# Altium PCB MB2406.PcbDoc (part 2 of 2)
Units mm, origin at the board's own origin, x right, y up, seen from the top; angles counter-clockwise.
Board outline 43 x 47 mm, 2 copper layers (Top Layer, Bottom Layer), stack 0.996 mm thick; 74 components, 55 nets, 319 pads, 911 vias.

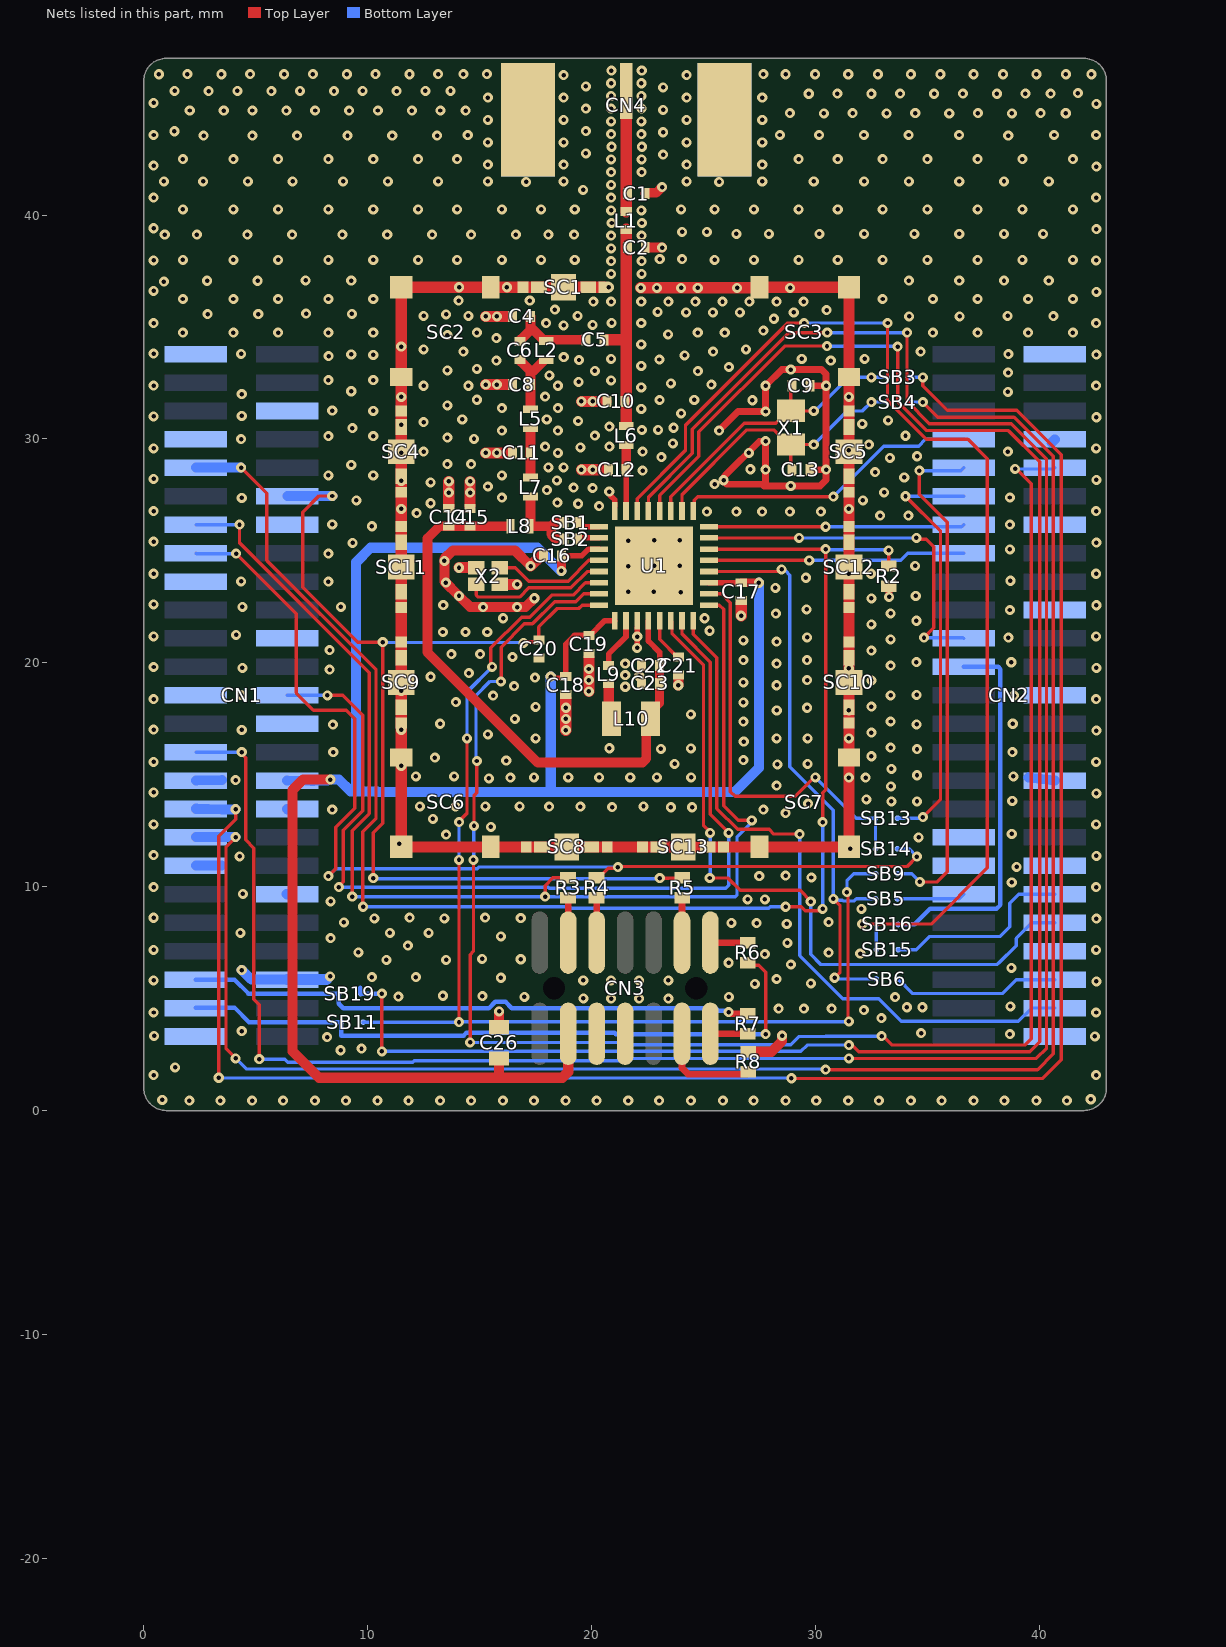
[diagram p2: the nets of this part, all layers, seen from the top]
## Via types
v1: diameter 0.45, hole 0.2, Top Layer to Bottom Layer, tented both sides, 911 vias

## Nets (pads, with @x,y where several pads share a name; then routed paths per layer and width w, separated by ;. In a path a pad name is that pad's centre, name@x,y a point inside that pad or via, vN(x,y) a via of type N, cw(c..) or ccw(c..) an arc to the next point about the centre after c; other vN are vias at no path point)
GND: C1.1 C2.1 C4.1 C8.1 C9.1 C10.1 C11.1 C12.1 C13.1 C14.2 C15.1 C16.1 C17.1 C18.1 C19.2 C20.1 C21.1 C22.1 C23.1 C26.1 CN1.1 CN1.6 CN1.7 CN1.14 CN1.17 CN1.22 CN1.25 CN1.28 CN1.31 CN1.34 CN1.37 CN1.40 CN1.46 CN1.49 CN2.2 CN2.8 CN2.14 CN2.20 CN2.26 CN2.32 CN2.38 CN2.44 CN2.50 CN3.5 CN3.7 CN4.2 CN4.3 CN4.4 CN4.5 R2.1 R8.1 SC1.1 SC2.1 SC3.1 SC4.1 SC5.1 SC6.1 SC7.1 SC8.1 SC9.1 SC10.1 SC11.1 SC12.1 SC13.1 U1.16 U1.27 U1.33 X2.2 X2.4 | length 148.5
  Top Layer w0.25: v1(20.793,27.649) 20.831,27.611 20.831,27.485 21.042,27.275 U1.16@21.042,27 ; v1(22.04,20.67) 22.041,20.671 v1(22.042,21.17) v1(22.042,21.17) U1.27@22.042,21.564
  Top Layer w0.3: v1@16.675,23.5 v1(16.68,23.505) ; v1(25.696,30.374) 26.547,31.225 v1(27.775,31.225) v1(27.775,32.375) 28.5,33.1 v1(28.9,33.1) 30.275,33.1 30.475,32.9 v1(30.475,32.375) ; C13.1@29.8,28.625 v1(30.475,28.625) ; C9.1@29.8,32.375 v1(30.475,32.375) ; R2.1@33.275,23.425 33.286,23.414 33.286,22.956 v1(33.297,22.945) ; 27.775,27.975 26.118,27.975 cw(c26.118,28.2) 25.959,28.359 27.491,29.891 27.766,29.891 v1(27.775,29.9) v1(27.775,28.625) 27.775,27.975 ; 27.775,27.975 27.7,27.9 v1(28.9,27.9) 30.214,27.9 30.475,28.161 v1(30.475,28.625) ; v1(30.475,28.625) v1(30.475,32.375)
  Top Layer w0.43: C1.1@22.4,40.961 22.4,40.981 22.415,40.996 22.895,40.996 23.15,41.25 v1(23.155,41.25) ; C2.1@22.45,38.55 v1(23.155,38.55)
  Top Layer w0.45: v1(14.08,24.245) v1@14.085,24.25 ; C26.1@15.875,3.725 v1(15.875,4.43) ; v1(17.275,24.32) 16.57,25.025 13.809,25.025 13.425,24.642 13.425,23.642 v1(14.08,22.988) 14.58,22.488 v1(15.155,22.488) v1(16.68,22.488) 17.053,22.488 v1(17.449,22.883) ; v1(23.874,18.996) 23.88,19.003 C21.1@23.88,19.339 ; R8.1@27.003,2.625 28.04,2.625 28.511,3.097 v1(28.511,3.34)
  Top Layer w0.5: C14.2@13.625,27 v1(13.625,27.6) v1(13.625,28.1) ; v1@14.085,24.25 X2.4@14.855,24.25 ; C15.1@14.575,27 v1(14.575,27.6) v1(14.575,28.1) ; v1(15.275,29.375) v1(15.775,29.375) C11.1@16.375,29.375 ; v1(15.275,32.425) v1(15.775,32.425) C8.1@16.375,32.425 ; v1(15.275,35.475) v1(15.775,35.475) C4.1@16.375,35.475 ; X2.2@15.905,23.5 v1@16.675,23.5 ; SC1.1@16.94,36.775 v1(16.22,36.775) SC2.1@15.5,36.775 SC2.1@11.5,36.775 v1(11.5,34.125) SC2.1@11.5,32.775 SC4.1@11.5,31.243 SC4.1@11.5,30.533 SC4.1@11.5,29.433 v1(11.5,29.375) SC4.1@11.5,28.333 SC4.1@11.5,27.623 SC11.1@11.5,26.088 SC11.1@11.5,25.378 SC11.1@11.5,24.278 SC11.1@11.5,23.178 SC11.1@11.5,22.468 SC9.1@11.5,20.93 SC9.1@11.5,20.22 SC9.1@11.5,19.12 SC9.1@11.5,18.02 SC9.1@11.5,17.31 SC6.1@11.5,15.775 v1(11.5,15.395) SC6.1@11.5,11.775 SC6.1@15.5,11.775 19.69,11.775 23.31,11.775 SC7.1@27.5,11.775 SC7.1@31.5,11.775 v1(31.5,14.875) SC7.1@31.5,15.775 v1(31.5,16.625) v1(31.5,17.875) v1(31.5,19.75) 31.5,22.464 SC12.1@31.5,22.468 SC12.1@31.5,23.178 v1(31.5,23.977) SC12.1@31.5,24.278 31.5,24.578 31.5,25.078 SC12.1@31.5,25.378 SC12.1@31.5,26.088 v1(31.5,26.875) SC5.1@31.5,27.623 SC5.1@31.5,28.333 SC5.1@31.5,29.433 SC5.1@31.5,30.533 SC5.1@31.5,31.243 SC3.1@31.5,32.775 SC3.1@31.5,36.775 SC3.1@27.5,36.775 ; SC1.1@16.94,36.775 SC1.1@17.65,36.775 SC1.1@18.75,36.775 SC1.1@19.85,36.775 SC1.1@20.56,36.775 ; v1(17.275,24.32) 17.731,24.776 C16.1@17.759,24.776 ; v1(18.852,16.99) v1(18.852,17.49) v1(18.852,17.99) C18.1@18.852,18.39 ; v1(19.55,28.625) v1(20.05,28.625) C12.1@20.65,28.625 ; v1(19.55,31.675) v1(20.05,31.675) C10.1@20.65,31.675 ; v1(19.882,18.723) v1(19.882,19.223) v1(19.882,19.723) C19.2@19.882,20.223 ; v1(22.2,36.75) v1(24.743,36.75) v1(26.5,36.75) SC3.1@27.475,36.75 ; v1(26.685,22.1) C17.1@26.685,22.675
  Bottom Layer w0.45: CN1.37@2.343,10.94 CN1.37@3.462,10.943 ; CN1.31@2.343,14.75 CN1.31@3.501,14.762 ; CN1.37@3.463,10.943 cw(c3.463,10.643) CN1.37@3.465,10.943 ; v1(4.375,6.275) 4.802,5.848 CN1.46@6.401,5.848 ; CN1.40@6.381,9.678 CN1.40@6.401,9.658 ; CN1.34@6.401,13.468 CN1.34@6.432,13.437 ; CN2.32@39.521,14.883 CN2.32@40.691,14.738 ; CN2.8@40.546,29.833 CN2.8@40.691,29.978
  Bottom Layer w0.5: CN1.46@6.401,5.848 8.16,5.848 v1@8.187,5.875
  other v1: 2.04,0.447 3.425,0.447 4.84,0.447 6.224,0.447 7.64,0.447 9.024,0.447 10.44,0.447 11.824,0.447 13.24,0.447 14.624,0.447 16.04,0.447 17.424,0.447 18.839,0.447 20.224,0.447 21.639,0.447 23.023,0.447 24.439,0.447 25.869,0.447 27.239,0.447 28.669,0.447 30.039,0.447 31.468,0.447 32.839,0.447 34.268,0.447 35.638,0.447 37.068,0.447 38.438,0.447 39.868,0.447 41.238,0.447 0.825,0.475 42.3,0.504 0.438,1.579 42.538,1.579 1.4,1.924 8.795,2.694 9.725,2.764 8.187,3.281 42.482,3.311 0.463,3.336 38.684,3.417 34.722,3.454 4.375,3.55 32.947,4.125 0.438,4.378 42.538,4.378 32.168,4.484 28.355,4.554 29.488,4.553 30.725,4.554 34.085,4.612 34.779,4.612 38.709,4.65 20.875,5 22.125,5 23.437,5 19.64,5.013 16.999,5.079 26.14,5.079 33.563,5.066 11.375,5.092 13.365,5.128 15.125,5.113 27.298,5.659 29.801,5.676 42.553,5.77 0.438,5.812 19.632,5.812 20.875,5.813 22.125,5.813 23.437,5.813 28.27,5.875 15.95,5.931 10.189,5.96 12.15,5.96 8.324,5.987 38.759,6.368 28.905,6.523 26.125,6.6 10.837,6.729 13.5,6.729 15.114,6.777 16.84,6.758 27.746,6.99 32.005,7.005 9.588,7.06 30.593,7.057 0.438,7.178 42.538,7.178 11.8,7.362 28.75,7.488 8.345,7.704 15.95,7.775 4.313,7.934 10.993,7.934 12.725,7.934 28.72,8.341 26.25,8.379 27.37,8.37 8.938,8.402 30.593,8.417 42.553,8.57 10.3,8.587 13.425,8.587 16.84,8.592 0.438,8.612 11.875,8.616 15.25,8.616 32.057,9.008 8.348,9.343 26.975,9.435 27.746,9.435 4.426,9.678 0.438,9.978 42.538,9.978 38.772,10.194 29.818,10.409 27.491,10.472 28.668,10.493 38.99,10.886 4.279,11.354 42.553,11.37 0.438,11.412 31.556,11.688 11.416,11.908 34.614,12.198 13.5,12.325 38.772,12.353 15.504,12.667 0.438,12.778 42.538,12.778 12.909,13.029 28.673,13.285 8.42,13.437 27.675,13.437 20.917,13.556 23.542,13.546 24.497,13.546 12.33,13.588 13.926,13.588 15.261,13.588 16.784,13.588 18.105,13.572 19.506,13.572 22.322,13.583 29.675,13.707 33.396,13.806 34.538,13.806 38.793,13.835 32.275,13.897 42.553,14.17 0.438,14.212 33.376,14.477 28.27,14.51 4.101,14.762 15.419,14.832 16.375,14.875 17.431,14.883 18.96,14.882 20.34,14.882 21.731,14.882 22.917,14.882 24.451,14.883 32.243,14.871 12.15,14.925 13.863,14.925 38.846,14.925 34.538,14.977 33.396,15.264 28.298,15.462 23.708,15.488 29.65,15.488 0.438,15.578 42.538,15.578 16.19,15.633 26.783,15.651 13,15.76 32.5,15.825 8.463,16.008 38.799,16.008 23.1,16.15 34.538,16.142 24.439,16.175 20.801,16.182 33.361,16.212 26.799,16.481 17.5,16.625 28.27,16.625 29.65,16.625 15.375,16.8 32.5,16.881 42.553,16.97 0.438,17.012 4.375,17 11.5,17 8.449,17.242 34.519,17.25 13.24,17.278 38.817,17.278 26.783,17.375 33.361,17.377 16.574,17.49 24.439,17.695 28.275,17.875 29.634,17.99 17.5,18.028 32.5,18.046 26.783,18.23 13.943,18.245 0.438,18.378 42.538,18.378 15.601,18.538 38.877,18.538 4.35,18.56 33.361,18.548 34.519,18.57 11.5,18.75 21.508,18.93 16.545,18.962 28.27,18.996 26.783,19.127 29.634,19.223 32.5,19.217 17.475,19.336 12.812,19.376 22.133,19.4 21.508,19.452 14.522,19.539 8.301,19.697 4.401,19.772 42.553,19.77 0.438,19.812 33.361,19.872 21.508,19.962 28.27,19.962 34.512,20.033 38.748,20.025 26.783,20.123 29.625,20.123 16.47,20.258 13.741,20.386 15.02,20.386 32.5,20.541 8.301,20.569 28.27,20.944 26.783,20.997 33.361,21.043 38.625,21.125 29.634,21.134 0.438,21.177 42.538,21.177 4.125,21.25 13.365,21.375 14.371,21.375 15.342,21.375 25.273,21.433 32.5,21.712 34.512,21.877 16.05,21.988 25.05,21.988 28.237,22.196 33.361,22.208 38.684,22.358 29.604,22.389 4.401,22.497 8.802,22.497 13.375,22.575 42.553,22.569 0.438,22.611 32.5,22.877 34.482,22.988 23.981,23.152 21.64,23.175 22.783,23.175 28.212,23.35 13.49,23.577 4.35,23.64 8.25,23.625 38.709,23.664 29.574,23.8 0.438,23.977 32.475,23.977 42.538,23.977 21.64,24.318 22.792,24.327 23.935,24.327 34.454,24.327 13.425,24.55 8.25,24.875 38.687,25.063 9.33,25.355 42.553,25.369 0.438,25.411 21.637,25.459 22.792,25.47 23.935,25.47 10.189,26.098 8.42,26.18 38.684,26.168 32.892,26.575 34.157,26.575 12.187,26.688 25.157,26.75 26.475,26.75 27.622,26.75 28.86,26.75 30.243,26.75 0.438,26.777 42.538,26.777 11.5,26.875 20.34,27 12.812,27.125 19.4,27.103 18.476,27.159 9.5,27.25 32.125,27.25 4.375,27.369 16,27.375 38.687,27.383 33.073,27.611 18.006,27.717 20.05,27.808 19.2,27.825 15.375,27.875 25.5,27.983 12.812,28.062 11.5,28.125 18.45,28.144 25.898,28.152 42.553,28.169 0.438,28.211 33.971,28.284 8.25,28.375 10.25,28.375 16,28.375 32.671,28.519 22.283,28.587 27.093,28.645 18.071,28.729 18.75,28.729 9.268,28.841 13.563,28.875 14.625,28.875 33.327,29.15 23.123,29.183 34.541,29.224 18.5,29.375 27.025,29.375 12.5,29.438 22.279,29.435 38.597,29.432 31.5,29.5 0.438,29.577 42.538,29.577 19.5,29.625 17.926,29.654 20.797,29.654 32.394,29.746 23.633,29.801 4.35,29.99 14.75,30 13.563,30.063 8.25,30.125 10.25,30.125 20.148,30.15 34.025,30.14 16,30.375 18.5,30.375 22.248,30.399 22.974,30.4 9.316,30.486 23.67,30.5 20.801,30.55 11.5,30.625 32.093,30.675 12.5,30.75 19.4,30.8 33.25,30.825 14.225,30.875 18,30.875 42.553,30.969 0.438,31.011 4.375,31.032 24,31.141 8.42,31.26 10.25,31.25 22.221,31.34 16,31.375 18.5,31.375 13.563,31.5 14.875,31.75 23.039,31.739 24.59,31.745 27.189,31.727 11.5,31.875 31.5,31.875 17.925,31.891 4.375,32 38.597,32.105 9.268,32.13 22.221,32.299 0.438,32.377 12.5,32.375 14.5,32.375 18.5,32.375 42.538,32.377 25.35,32.425 23.542,32.477 19.425,32.55 8.25,32.625 10.25,32.625 20.879,32.615 18.121,32.837 38.613,32.959 20.15,33.038 24.748,33.028 13.563,33.062 14.875,33.125 26.14,33.212 22.221,33.259 15.75,33.5 30.686,33.5 19.44,33.525 23.03,33.548 20.879,33.575 29.39,33.575 32.199,33.575 18.76,33.65 8.256,33.7 24.155,33.73 10.25,33.75 9.268,33.775 42.553,33.769 4.35,33.8 38.625,33.788 0.438,33.811 14.273,33.897 25.432,33.897 34.702,33.897 12.5,34 26.9,34 22.221,34.219 15.75,34.5 13.563,34.635 23.425,34.673 1.75,34.75 4,34.75 6,34.75 8.25,34.75 10.25,34.75 14.875,34.75 24.746,34.75 25.95,34.75 35.25,34.75 37.25,34.75 39.5,34.75 41.5,34.75 27.675,34.839 18.75,35.068 20.05,35.097 0.438,35.177 17.975,35.173 22.221,35.178 42.538,35.177 20.895,35.187 28.143,35.369 34.186,35.475 36.446,35.475 40.629,35.484 12.5,35.5 14.5,35.5 19.375,35.5 38.585,35.494 2.854,35.579 5.114,35.579 13.5,35.562 7.253,35.598 9.297,35.589 24.221,35.653 25.425,35.653 26.625,35.65 29.033,35.65 22.954,35.676 30.5,35.75 18.359,35.772 20.087,36.138 20.879,36.138 22.221,36.138 23.43,36.138 24.64,36.138 25.85,36.138 27.055,36.138 28.265,36.138 29.474,36.138 14.062,36.175 17.239,36.175 1.75,36.25 4,36.25 6,36.25 8.25,36.25 10.25,36.25 33,36.25 35.25,36.25 37.25,36.25 39.5,36.25 41.5,36.25 42.553,36.569 0.438,36.611 22.917,36.75 24,36.75 28.875,36.75 14.085,36.775 20.775,36.775 0.9,37.025 2.825,37.066 5.085,37.066 9.268,37.075 34.175,37.075 36.425,37.075 38.425,37.075 40.425,37.075 7.224,37.085 20.879,37.375 22.233,37.375 20.879,37.943 22.233,37.943 0.438,37.976 42.538,37.976 1.75,38 4,38 6,38 8.25,38 10.25,38 12.25,38 14,38 16,38 17.75,38 19.25,38 25.5,38 27.25,38 29.25,38 31,38 33,38 35,38 37.25,38 39.25,38 41.5,38 23.048,38.029 24.05,38.029 20.879,38.51 20.879,39.078 22.233,39.078 0.936,39.125 2.375,39.125 4.625,39.125 6.625,39.125 8.875,39.125 10.875,39.125 12.875,39.125 14.625,39.125 16.625,39.125 18.073,39.125 19.224,39.125 26.475,39.156 27.925,39.156 30.175,39.156 32.175,39.156 34.425,39.156 36.425,39.156 38.425,39.156 40.175,39.156 24.05,39.25 25.15,39.25 42.553,39.368 0.438,39.41 20.895,39.645 22.249,39.645 20.875,40.213 22.229,40.213 1.75,40.25 4,40.25 6,40.25 8.25,40.25 10.25,40.25 12.25,40.25 14,40.25 16,40.25 17.75,40.25 19.25,40.25 24,40.25 25.5,40.25 27.25,40.25 29.25,40.25 31,40.25 33,40.25 35,40.25 37.25,40.25 39.25,40.25 41.5,40.25 0.438,40.776 20.879,40.78 42.538,40.776 19.625,41.125 20.879,41.347 17.076,41.477 25.701,41.477 0.9,41.5 2.65,41.5 4.65,41.5 6.65,41.5 8.9,41.5 10.9,41.5 13.15,41.5 15.375,41.5 18.75,41.5 24.25,41.5 27.625,41.5 29.925,41.5 32.175,41.5 34.175,41.5 36.425,41.5 38.425,41.5 40.425,41.5 20.879,41.915 22.233,41.915 42.553,42.168 0.438,42.21 15.375,42.25 18.75,42.25 24.25,42.25 27.625,42.25 20.879,42.482 22.233,42.482 1.75,42.5 4,42.5 6,42.5 8.25,42.5 10.25,42.5 12.25,42.5 14,42.5 29.25,42.5 31,42.5 33,42.5 35,42.5 37.25,42.5 39.25,42.5 41.5,42.5 23.2,42.7 19.75,42.75 20.895,43.05 22.249,43.05 15.375,43.25 18.75,43.25 24.25,43.25 27.625,43.25 2.675,43.55 4.85,43.55 6.85,43.55 9.1,43.55 11.1,43.55 13.1,43.55 38.616,43.551 0.438,43.576 14.471,43.575 28.416,43.576 30.166,43.576 32.166,43.576 34.166,43.576 36.416,43.576 40.666,43.576 42.538,43.576 20.875,43.617 22.229,43.617 23.2,43.7 1.369,43.744 19.75,43.75 20.875,44.185 22.229,44.185 15.375,44.25 18.75,44.25 24.25,44.25 27.625,44.25 28.86,44.55 30.379,44.543 31.66,44.55 33.179,44.543 34.46,44.55 35.979,44.543 37.26,44.55 38.779,44.543 40.06,44.55 41.182,44.547 2.053,44.67 3.572,44.663 4.853,44.67 6.372,44.663 7.653,44.67 9.172,44.663 10.453,44.67 11.972,44.663 13.252,44.67 14.375,44.667 23.2,44.7 19.75,44.75 20.875,44.752 22.229,44.752 42.553,44.968 0.438,45.01 15.375,45.25 18.75,45.25 24.25,45.25 27.625,45.25 20.875,45.32 22.229,45.32 29.704,45.418 30.985,45.425 32.504,45.418 33.785,45.425 35.304,45.418 36.585,45.425 38.104,45.418 39.385,45.425 40.507,45.422 41.725,45.45 2.897,45.538 5.697,45.538 8.497,45.538 11.297,45.538 13.7,45.542 1.378,45.545 4.178,45.545 6.978,45.545 9.778,45.545 12.577,45.545 23.2,45.7 19.75,45.75 20.875,45.887 22.229,45.887 18.75,46.25 24.25,46.25 0.67,46.288 1.951,46.295 3.47,46.288 4.751,46.295 6.27,46.288 7.55,46.295 9.069,46.288 10.35,46.295 11.869,46.288 13.15,46.295 14.273,46.292 15.325,46.3 27.675,46.3 28.668,46.288 29.988,46.288 31.468,46.288 32.787,46.288 34.268,46.288 35.587,46.288 37.068,46.288 38.387,46.288 39.868,46.288 41.187,46.288 42.328,46.288 20.891,46.455 22.245,46.455
GPIO3/BOOT0: CN1.9 R2.2 U1.6 | length 69.9
  Top Layer w0.15: v1(4.35,28.72) 5.49,27.58 5.49,24.569 10.375,19.684 10.375,13.061 9.775,12.461 9.775,9.127 v1(9.8,9.102) ; U1.6@25.242,25.077 v1(30.457,25.077) 30.457,14.323 30.325,14.192 v1(30.325,12.886) ; v1(28.673,9.102) 29.372,9.102 29.546,8.928 30.164,8.928 30.244,9.008 v1(30.325,9.008) ; R2.2@33.275,24.325 v1(33.275,25.019)
  Bottom Layer w0.15: v1(9.8,9.102) 18.892,9.102 18.959,9.035 27.912,9.035 27.979,9.102 v1(28.673,9.102) ; v1(30.325,9.008) v1(30.325,12.886) ; v1@30.457,25.063 30.471,25.048 33.246,25.048 v1(33.275,25.019)
  Bottom Layer w0.45: CN1.9@2.343,28.72 v1(4.35,28.72)
GPIO5/SWDIO: CN1.13 R3.2 U1.1 | length 54.8
  Top Layer w0.15: v1(4.275,26.168) 4.275,25.36 10.075,19.56 10.075,13.267 9.313,12.505 v1(9.313,9.555) ; v1(17.925,9.555) 17.925,10.049 18.276,10.4 R3.2@18.95,10.4 ; U1.1@25.242,22.577 25.712,22.577 25.9,22.389 25.9,13.615 26.554,12.961 v1(27.158,12.961)
  Bottom Layer w0.15: CN1.13@2.331,26.168 v1(4.275,26.168) ; v1(9.313,9.555) 26.412,9.555 26.5,9.643 26.5,12.222 27.158,12.88 v1(27.158,12.961)
GPIO6/SWCLK: CN1.15 R4.2 SB14.1 | length 48.5
  Top Layer w0.15: v1(4.126,24.875) 6.805,22.196 6.805,18.65 7.579,17.875 9.05,17.875 9.425,17.5 9.425,13.509 8.575,12.659 8.575,10.8 v1(8.25,10.475) ; R4.2@20.225,10.4 20.32,10.4 20.738,10.818 21.118,10.818 21.2,10.9 34.094,10.9 v1(34.532,11.338)
  Bottom Layer w0.15: CN1.15@2.331,24.898 2.354,24.875 v1(4.126,24.875) ; v1(8.25,10.475) 8.575,10.8 14.891,10.8 14.966,10.875 v1(21.175,10.875) ; SB14.1@33.662,11.688 34.182,11.688 v1(34.532,11.338)
GPIO12: CN1.26 U1.31 | length 42
  Top Layer w0.15: v1(8.2,18.548) 8.885,18.548 9.775,17.658 9.775,13.392 8.908,12.524 8.908,10.216 8.712,10.021 v1(8.712,9.978) ; U1.31@24.042,21.877 24.042,21.292 25.3,20.033 25.3,13.225 v1(26.125,12.4)
  Bottom Layer w0.15: CN1.26@6.401,18.548 v1(8.2,18.548) ; v1(8.712,9.978) 18.067,9.978 18.111,9.934 25.993,9.934 26.125,10.066 v1(26.125,12.4)
GPIO14: CN1.29 U1.13 | length 104.1
  Top Layer w0.15: v1(4.375,16.008) 4.375,15.927 4.55,15.752 4.55,12.088 4.916,11.722 4.916,4.962 5.158,4.719 v1(5.158,2.294) ; U1.13@22.542,26.777 22.545,26.78 22.545,27.402 24.497,29.355 24.497,30.438 28.809,34.75 v1(30.531,34.75) ; v1(31.5,2.325) 39.861,2.325 40.325,2.789 40.325,29.1 38.75,30.675 35.093,30.675 34.094,31.674 v1(34.094,34.75)
  Bottom Layer w0.15: CN1.29@2.331,16.008 v1(4.375,16.008) ; v1(5.158,2.294) 6.296,2.294 6.432,2.158 12.02,2.158 12.087,2.225 21.703,2.225 21.803,2.325 v1(31.5,2.325) ; v1(30.531,34.75) v1(34.094,34.75)
GPIO15/OSC32_IN: CN1.33 SB3.2 | length 87.6
  Top Layer w0.15: v1(3.35,1.463) 3.35,12.256 4.101,13.007 v1(4.101,13.457) ; v1(28.928,1.443) 28.944,1.428 40.128,1.428 40.975,2.275 40.975,29.299 38.999,31.275 35.891,31.275 34.8,32.366 v1(34.8,32.747)
  Bottom Layer w0.15: v1(3.35,1.463) 3.36,1.453 28.919,1.453 v1(28.928,1.443) ; SB3.2@34.1,32.747 SB3.2@34.175,32.747 v1(34.8,32.747)
  Bottom Layer w0.45: CN1.33@2.343,13.48 3.501,13.437 4.081,13.437 v1(4.101,13.457)
GPIO16/OSC32_OUT: CN1.35 SB4.2 | length 83.2
  Top Layer w0.15: v1(4.101,2.325) 3.675,2.751 3.675,11.784 v1(4.101,12.21) ; v1(30.457,1.828) 39.924,1.828 40.625,2.529 40.625,29.224 38.874,30.975 35.472,30.975 v1(34.8,31.647)
  Bottom Layer w0.15: v1(4.101,2.325) 4.568,1.858 30.427,1.858 v1(30.457,1.828) ; SB4.2@34.1,31.647 SB4.2@34.175,31.647 v1(34.8,31.647)
  Bottom Layer w0.45: CN1.35@2.343,12.21 v1(4.101,12.21)
GPIO23/VCP1_RX: CN1.45 R7.1 SB19.2 | length 25.8
  Top Layer w0.3: v1(26.125,4.4) 26.166,4.4 26.241,4.325 R7.1@26.975,4.325
  Bottom Layer w0.2: CN1.45@2.331,5.848 4.052,5.848 4.675,5.225 SB19.2@8.712,5.225 8.712,4.77 8.908,4.575 15.419,4.575 15.699,4.855 16.159,4.855 16.439,4.575 25.55,4.575 25.677,4.448 26.077,4.448 v1(26.125,4.4)
GPIO24/VCP1_TX: CN1.47 R6.2 SB11.1 | length 30.1
  Top Layer w0.15: R6.2@26.975,6.6 27.085,6.49 27.462,6.49 27.775,6.177 v1(27.775,3.417)
  Bottom Layer w0.2: CN1.47@2.331,4.598 4.052,4.598 4.7,3.95 SB11.1@8.825,3.95 8.825,3.35 14.284,3.35 14.399,3.465 21.029,3.465 21.078,3.417 v1(27.775,3.417)
GPIO28: CN2.7 U1.9 | length 13.7
  Top Layer w0.15: U1.9@24.542,26.777 24.592,26.827 24.592,27.265 24.747,27.42 v1(30.8,27.42)
  Bottom Layer w0.15: v1(30.8,27.42) 33.055,29.675 34.614,29.675 34.917,29.978 CN2.7@36.621,29.978
GPIO29: CN2.9 SB9.1 | length 23
  Top Layer w0.15: v1(34.647,28.585) 34.647,27.525 35.891,26.281 35.891,10.66 35.441,10.21 v1(34.667,10.21)
  Bottom Layer w0.15: SB9.1@33.662,10.582 34.297,10.582 v1(34.667,10.21) v1(34.667,10.21) ; v1(34.647,28.585) 36.498,28.585 CN2.9@36.621,28.708
GPIO30: CN2.10 U1.23 | length 77
  Top Layer w0.15: v1(14.575,3.04) 14.575,6.959 14.725,7.109 v1(14.725,11.2) ; v1(14.75,12.711) 14.75,14.071 14.875,14.196 v1(14.875,15.613) ; v1(15.95,19.164) 15.96,19.174 15.96,20.699 16.999,21.738 17.363,21.738 18.351,22.725 19.303,22.725 19.654,23.077 U1.23@20.342,23.077 ; v1(32.957,3.325) 33.036,3.325 33.436,2.925 39.35,2.925 39.637,3.212 39.637,27.995 38.976,28.657 v1(38.921,28.657)
  Bottom Layer w0.15: v1(14.575,3.04) 21.731,3.04 21.831,2.94 28.905,2.94 29.273,3.308 30.438,3.308 30.455,3.325 v1(32.957,3.325) ; v1(14.725,11.2) 14.737,11.212 14.737,12.699 v1(14.75,12.711) ; v1(14.875,15.613) 14.837,15.651 14.837,18.538 15.463,19.164 v1(15.95,19.164) ; v1(38.921,28.657) 40.64,28.657 CN2.10@40.691,28.708
GPIO31: CN2.11 SB13.1 | length 19.1
  Top Layer w0.15: v1(34.025,27.438) 35.591,25.872 35.591,13.898 v1(34.8,13.107)
  Bottom Layer w0.15: SB13.1@33.662,13.061 34.754,13.061 v1(34.8,13.107) ; v1(34.025,27.438) CN2.11@36.621,27.438
GPIO33: CN2.13 U1.8 | length 11.4
  Top Layer w0.15: U1.8@25.242,26.077 v1(30.457,26.077)
  Bottom Layer w0.15: v1(30.457,26.077) 32.947,26.077 32.949,26.075 36.528,26.075 CN2.13@36.621,26.168
GPIO34: CN2.15 U1.5 | length 11.5
  Top Layer w0.15: U1.5@25.242,24.577 25.243,24.576 29.724,24.576 v1(29.725,24.575)
  Bottom Layer w0.15: v1(29.725,24.575) 33.808,24.575 34.131,24.898 CN2.15@36.621,24.898
GPIO37: CN2.21 U1.7 | length 16.2
  Top Layer w0.15: U1.7@25.242,25.577 v1(29.273,25.577) ; v1(34.512,25.577) 34.57,25.52 34.962,25.52 35.291,25.19 35.291,21.565 v1(34.851,21.125)
  Bottom Layer w0.15: v1(29.273,25.577) v1(34.512,25.577) ; v1(34.851,21.125) 36.584,21.125 CN2.21@36.621,21.088
GPIO39: CN2.23 SB16.1 | length 17.2
  Bottom Layer w0.2: SB16.1@33.7,8.313 34.444,8.313 34.444,8.329 35.122,9.008 38.09,9.008 38.266,9.184 38.266,19.715 38.163,19.818 CN2.23@36.621,19.818
GPIO47: CN2.35
GPIO49: CN2.37
GPIO50: CN2.39 SB5.1 | length 3
  Bottom Layer w0.15: SB5.1@33.662,9.452 36.415,9.452 CN2.39@36.621,9.658
GPIO51: CN2.40 SB15.1 | length 8.6
  Bottom Layer w0.15: SB15.1@33.7,7.187 34.512,7.187 35.1,7.775 38.259,7.775 38.684,8.2 38.684,9.263 39.08,9.658 CN2.40@40.691,9.658
GPIO53: CN2.42 U1.30 | length 31.6
  Top Layer w0.15: U1.30@23.542,21.877 23.592,21.827 23.592,21.318 25,19.909 25,12.74 25.296,12.444 v1(25.296,12.4) ; v1(25.281,10.387) 26.086,10.387 26.637,9.835 29.315,9.835 29.793,9.357 v1(29.793,9.328)
  Bottom Layer w0.15: v1(25.281,10.387) 25.301,10.407 25.301,12.395 v1(25.296,12.4) ; v1(29.793,9.328) 29.788,9.323 29.788,6.975 30.24,6.523 38.109,6.523 38.163,6.577 38.179,6.577 38.965,7.362 38.965,7.687 39.666,8.388 CN2.42@40.691,8.388
GPIO56: CN2.46 SB6.1 | length 7.5
  Bottom Layer w0.15: SB6.1@33.696,5.875 34.346,5.225 38.342,5.225 38.965,5.848 CN2.46@40.691,5.848
GPIO57: CN2.48 U1.32 | length 31.3
  Top Layer w0.15: U1.32@24.542,21.877 24.542,21.281 25.6,20.223 25.6,13.491 26.53,12.561 27.932,12.561 28.143,12.35 v1(29.299,12.35)
  Bottom Layer w0.15: v1(29.299,12.35) 29.299,6.923 31.222,5 32.826,5 33.843,3.983 39.071,3.983 39.666,4.578 CN2.48@40.691,4.578
NetC1_2: C1.2 CN4.1 L1.2 | length 5.4
  Top Layer w0.51: L1.2@21.55,40.156 CN4.1@21.55,45.55
NetC2_2: C2.2 C5.2 C10.2 L1.1 L6.2 | length 9.5
  Top Layer w0.51: C5.2@20.702,34.425 21.55,34.425 ; L6.2@21.55,30.701 21.55,31.675 21.55,34.425 ; 21.55,37.274 21.55,34.425 ; 21.55,37.275 21.55,37.775 21.55,38.55 L1.1@21.55,39.356
NetC4_2: C4.2 C5.1 C6.2 L2.2 | length 3.9
  Top Layer w0.43: C6.2@16.8,34.4 16.825,34.4 16.865,34.44 16.865,34.465 17.275,34.875 C4.2@17.275,35.475 ; 17.337,34.937 17.85,34.425 C5.1@19.724,34.425
NetC6_1: C6.1 C8.2 L2.1 L5.2 | length 3.1
  Top Layer w0.43: C6.1@16.8,33.5 16.825,33.5 16.865,33.46 16.865,33.435 17.275,33.025 ; L5.2@17.275,31.404 C8.2@17.275,32.425 17.275,33.01 17.29,33.025 17.4,33.025 L2.1@17.85,33.475
NetC9_2: C9.2 SB3.1 U1.11 X1.2 | length 13.8
  Top Layer w0.15: U1.11@23.542,26.777 23.542,27.426 26.815,30.7 28.237,30.7 28.35,30.813 28.35,30.825 28.775,31.25 X1.2@28.9,31.25 ; C9.2@28.9,32.375 X1.2@28.9,31.25 ; v1@30.075,31.25 X1.2@28.9,31.25
  Bottom Layer w0.15: v1(29.925,31.25) 30,31.25 31.497,32.747 v1(32.5,32.747) SB3.1@33.2,32.747
NetC11_2: C11.2 L5.1 L7.2 | length 2
  Top Layer w0.43: L7.2@17.275,28.325 17.275,28.355 L5.1@17.275,30.329
NetC12_2: C12.2 L6.1 U1.15 | length 2.9
  Top Layer w0.25: U1.15@21.55,26.777 C12.2@21.55,28.625
  Top Layer w0.43: C12.2@21.55,28.625 L6.1@21.55,29.675
NetC13_2: C13.2 SB4.1 U1.10 X1.1 | length 13.3
  Top Layer w0.15: U1.10@24.042,26.777 24.042,27.502 26.939,30.4 28.149,30.4 28.35,30.199 28.35,30.175 28.775,29.75 X1.1@28.9,29.75 ; C13.2@28.9,28.625 X1.1@28.9,29.75 ; v1(29.925,29.75) X1.1@28.9,29.75
  Bottom Layer w0.15: v1(29.925,29.75) 31.422,31.247 32.1,31.247 v1(32.5,31.647) SB4.1@33.2,31.647
NetC21_2: C21.2 U1.29 | length 2
  Top Layer w0.15: U1.29@23.042,21.877 23.042,21.049 23.833,20.258 C21.2@23.883,20.258
NetCN3_4: CN3.4 R3.1 | length 2
  Top Layer w0.3: R3.1@18.95,9.5 18.96,9.49 CN3.4@18.96,7.5
NetCN3_6: CN3.6 R4.1 | length 2
  Top Layer w0.3: R4.1@20.225,9.5 20.23,9.495 CN3.6@20.23,7.5
NetCN3_11: CN3.11 R8.2 | length 4.7
  Top Layer w0.3: CN3.11@24.04,3.43 24.04,1.897 24.312,1.625 26.903,1.625 R8.2@27.003,1.725 ; R8.2@26.914,1.814 R8.2@26.928,1.828
NetCN3_12: CN3.12 R5.1 | length 2
  Top Layer w0.3: CN3.12@24.04,7.5 24.04,9.49 R5.1@24.05,9.5
NetCN3_13: CN3.13 R7.2 | length 1.7
  Top Layer w0.3: CN3.13@25.31,3.43 25.315,3.425 R7.2@26.975,3.425
NetCN3_14: CN3.14 R6.1 | length 1.7
  Top Layer w0.3: CN3.14@25.31,7.5 R6.1@26.975,7.5
NetL7_1: L7.1 L8.2 SB1.2 SB2.2 | length 3.8
  Top Layer w0.43: L7.1@17.275,27.375 17.275,26.1 18.193,26.1 ; SB1.2@18.698,26.266 18.359,26.266 18.193,26.1 ; SB2.2@18.76,25.535 18.399,25.535 18.193,25.74 18.193,26.1
NetL9_1: L9.1 L10.2 | length 1.1
  Top Layer w0.47: L10.2@20.765,17.935 L9.1@20.765,18.993
NetL9_2: L9.2 U1.26 | length 2.3
  Top Layer w0.25: L9.2@20.765,19.921 20.765,20.386 21.542,21.163 U1.26@21.542,21.877
NetSB1_1: SB1.1 U1.17 | length 1
  Top Layer w0.25: SB1.1@19.375,26.266 ccw(c19.832,26.723) 19.832,26.077 U1.17@20.342,26.077
NetSB2_1: SB2.1 U1.18 | length 1
  Top Layer w0.25: SB2.1@19.375,25.525 19.427,25.577 U1.18@20.342,25.577
NetSB5_2: SB5.2 SB6.2 U1.4 | length 26.6
  Top Layer w0.15: U1.4@25.242,24.077 28.315,24.077 28.414,24.176 v1(28.495,24.176) ; v1(30.8,9.452) 31.101,9.151 31.101,6.176 v1(30.856,5.931)
  Bottom Layer w0.15: v1(28.495,24.176) 28.577,24.176 28.648,24.105 28.668,24.105 28.86,23.913 28.86,15.352 30.8,13.412 v1(30.8,9.452) 30.857,9.395 31.21,9.395 31.244,9.361 31.744,9.361 31.835,9.452 SB5.2@32.687,9.452 ; v1(30.856,5.931) 30.913,5.875 SB6.2@32.721,5.875
NetSB9_2: SB9.2 SB11.2 U1.22 | length 52.8
  Top Layer w0.15: v1(14.08,3.95) v1(14.08,11.2) ; v1(14.085,12.886) 14.085,12.933 14.437,13.285 v1(14.437,16.625) ; v1(15.56,19.818) 15.504,19.874 15.504,20.667 16.875,22.038 17.239,22.038 18.227,23.025 19.178,23.025 19.73,23.577 U1.22@20.342,23.577 ; v1(31.41,9.761) 31.455,9.715 31.455,4.028 v1(31.5,3.983)
  Bottom Layer w0.15: SB11.2@9.8,3.95 v1(14.08,3.95) 14.096,3.966 31.484,3.966 v1(31.5,3.983) ; v1(14.08,11.2) 14.083,11.202 14.083,12.884 v1(14.085,12.886) ; v1(14.437,16.625) 14.437,18.695 v1(15.56,19.818) ; v1(31.41,9.761) 31.41,10.272 31.72,10.582 SB9.2@32.687,10.582
NetSB13_2: SB13.2 SB14.2 U1.2 | length 18.6
  Top Layer w0.15: U1.2@25.242,23.077 25.808,23.077 26.2,22.685 26.2,14.246 26.411,14.035 29.102,14.035 29.95,14.883 v1(30,14.883)
  Bottom Layer w0.15: v1(30,14.883) 31.822,13.061 SB13.2@32.687,13.061 SB14.2@32.687,11.688
NetSB15_2: SB15.2 SB16.2 U1.14 | length 51.3
  Top Layer w0.15: U1.14@22.042,26.777 22.042,27.33 24.197,29.486 24.197,30.606 28.77,35.178 v1(29.5,35.178) ; v1(32.093,8.329) 35.168,8.329 37.675,10.836 37.675,29.12 36.817,29.978 34.941,29.978 33.222,31.697 v1(33.222,35.178)
  Bottom Layer w0.15: v1(29.5,35.178) v1(33.222,35.178) ; v1(32.093,8.329) 32.109,8.313 SB16.2@32.725,8.313 SB15.2@32.725,7.187
NetSB19_1: SB19.1 U1.12 | length 84.1
  Top Layer w0.15: v1(10.632,2.64) v1(10.632,5.226) ; U1.12@23.042,26.777 23.042,27.475 24.797,29.23 24.797,30.314 28.633,34.15 v1(30.518,34.15) ; v1(31.5,2.925) 31.557,2.868 31.7,2.868 31.942,2.625 39.58,2.625 40.025,3.07 40.025,26.088 40.015,26.098 40.015,28.986 38.626,30.375 34.969,30.375 33.675,31.669 v1(33.675,34.125)
  Bottom Layer w0.15: v1(10.632,2.64) 29.349,2.64 29.634,2.925 v1(31.5,2.925) ; v1(30.518,34.15) 30.531,34.137 33.663,34.137 v1(33.675,34.125)
  Bottom Layer w0.2: 9.677,5.487 9.677,5.271 SB19.1@9.687,5.26 ; SB19.1@9.687,5.225 v1(10.632,5.226)
NetU1_20: U1.20 X2.3 | length 5.1
  Top Layer w0.15: X2.3@15.905,24.25 16.597,24.25 17.197,23.65 18.955,23.65 19.882,24.577 U1.20@20.342,24.577
NetU1_21: U1.21 X2.1 | length 6.5
  Top Layer w0.15: X2.1@14.855,23.5 14.855,23.025 14.943,22.938 16.784,22.938 17.197,23.35 19.079,23.35 19.806,24.077 U1.21@20.342,24.077
NRST: C20.2 CN1.12 R5.2 U1.24 | length 46.8
  Top Layer w0.15: v1(8.42,27.45) 7.825,27.45 7.105,26.73 7.105,23.379 9.561,20.922 v1(10.675,20.922) 10.675,12.834 10.25,12.409 v1(10.25,10.378) ; v1(16.958,20.887) 17.016,20.945 17.576,20.945 C20.2@17.65,21.019 17.65,21.6 18.476,22.425 19.427,22.425 19.579,22.577 U1.24@20.342,22.577 ; v1(23.048,10.378) 24.028,10.378 R5.2@24.05,10.4
  Bottom Layer w0.15: v1(10.25,10.378) 10.281,10.347 23.017,10.347 v1(23.048,10.378) ; v1(10.675,20.922) 10.692,20.905 16.941,20.905 v1(16.958,20.887)
  Bottom Layer w0.45: CN1.12@6.413,27.45 v1(8.42,27.45)
VDD: C16.2 C17.2 C18.2 C19.1 C26.2 CN1.32 CN3.3 U1.3 U1.19 U1.25 | length 94.6
  Top Layer w0.2: v1(18.18,19.379) 18.192,19.285 cw(c18.316,19.161) 18.316,19.336 18.695,19.336 18.853,19.339 C18.2@18.875,19.339 ; C18.2@18.875,19.34 18.875,20.296
  Top Layer w0.25: v1@18.624,24.105 v1@18.637,24.117 ; C16.2@18.637,24.763 C16.2@18.65,24.776 19.557,24.776 19.858,25.077 U1.19@20.342,25.077 ; C18.2@18.853,19.339 18.853,20.836 19.239,21.223 C19.1@19.882,21.223 19.932,21.223 20.586,21.877 U1.25@21.042,21.877 ; U1.3@25.242,23.577 26.683,23.577 C17.2@26.685,23.575
  Top Layer w0.4: v1(18.65,24.105) C16.2@18.65,24.776 ; C17.2@26.685,23.575 v1(27.475,23.575)
  Top Layer w0.45: v1(8.338,14.778) 7.105,14.778 6.65,14.323 6.65,2.64 7.825,1.465 15.875,1.465 ; C26.2@15.875,2.325 15.875,1.465 ; CN3.3@18.96,3.43 18.96,1.733 18.692,1.465 15.875,1.465
  Bottom Layer w0.45: CN1.32@6.401,14.738 7.503,14.712 ccw(c7.509,15.012) CN1.32@7.63,14.738 ; CN1.32@7.63,14.75 8.179,14.75 ccw(c8.179,15.05) v1@8.244,14.757 ; v1(8.338,14.778) 8.718,14.778 9.239,14.257 10.434,14.257 10.463,14.229 18.18,14.229 23.532,14.229 26.401,14.229 27.475,15.304 27.475,19.439 v1(27.475,23.575) ; 9.487,14.461 9.487,24.496 10.132,25.14 17.589,25.14 18.624,24.105 v1(18.65,24.105) ; 18.18,14.257 v1(18.18,19.379)
VFBSD: C14.1 C15.2 C22.2 C23.2 L8.1 L10.1 U1.28 | length 27.3
  Top Layer w0.25: U1.28@22.542,21.877 22.542,20.973 23.048,20.467 C22.2@23.048,20.025
  Top Layer w0.4: L10.1@22.446,17.505 22.446,17.606 23.033,18.193 C23.2@23.033,19.077 23.033,19.127 C22.2@23.033,19.873
  Top Layer w0.43: L8.1@16.272,26.1 C15.2@14.575,26.1 C14.1@13.625,26.1 13.21,26.1 12.674,25.564 12.674,20.467 17.595,15.546 22.276,15.546 22.446,15.716 L10.1@22.446,17.505
pads on no net: CART-1.1 CN1.2 CN1.3 CN1.4 CN1.5 CN1.8 CN1.10 CN1.11 CN1.16 CN1.18 CN1.19 CN1.20 CN1.21 CN1.23 CN1.24 CN1.27 CN1.30 CN1.36 CN1.38 CN1.39 CN1.41 CN1.42 CN1.43 CN1.44 CN1.48 CN1.50 CN2.1 CN2.3 CN2.4 CN2.5 CN2.6 CN2.12 CN2.16 CN2.17 CN2.18 CN2.19 CN2.22 CN2.24 CN2.25 CN2.27 CN2.28 CN2.29 CN2.30 CN2.31 CN2.33 CN2.34 CN2.36 CN2.41 CN2.43 CN2.45 CN2.47 CN2.49 CN3.1 CN3.2 CN3.8 CN3.9 CN3.10 CN3.NPTH1 CN3.NPTH2

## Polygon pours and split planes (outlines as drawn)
GND on Top Layer "GND_L01_P001" (solid, remove dead copper, pour order 1): 0,47 43,47 43,0 0,0
GND on Top Layer "GND_L01_P004" (solid, remove dead copper, pour order 4): 14.496,29.375 14.5,29.371 14.5,27.35 14.787,27.063 16.625,27.063 16.625,29.375
GND on Bottom Layer "GAGND_L02_P003" (solid, remove dead copper, pour order 3): 0,47 43,47 43,0 0,0

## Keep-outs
Top Layer:
  region: 21.207,31.141 19.559,31.141 cw(c19.559,31.675) 19.025,31.675 cw(c19.55,31.675) 19.55,32.2 21.207,32.2
  region: 16.625,34.941 15.284,34.941 cw(c15.284,35.475) 14.75,35.475 cw(c15.275,35.475) 15.275,36 16.625,36 16.625,35.85
  region: 22,28.091 19.559,28.091 cw(c19.559,28.625) 19.025,28.625 cw(c19.55,28.625) 19.55,29.15 22,29.15
  region: 14.155,23.87 14.08,23.87 cw(c14.08,24.25) 13.7,24.25 cw(c14.075,24.25) 14.075,24.625 15.225,24.625 15.225,23.875
  region: 13.091,26.75 13.091,28.091 cw(c13.625,28.091) 13.625,28.625 cw(c13.625,28.1) 14.15,28.1 14.15,26.75 14,26.75
  region: 17.275,31.891 15.284,31.891 cw(c15.284,32.425) 14.75,32.425 cw(c15.275,32.425) 15.275,32.95 17.275,32.95
  region: 17.275,28.841 15.284,28.841 cw(c15.284,29.375) 14.75,29.375 cw(c15.275,29.375) 15.275,29.9 17.275,29.9
  region: 14.041,26.75 14.041,28.091 cw(c14.575,28.091) 14.575,28.625 cw(c14.575,28.1) 15.1,28.1 15.1,26.75 14.95,26.75
  region: 15.954,24.804 19.448,24.804 19.448,25.74 15.954,25.74
Keep-Out Layer:
  lines w0.1: 0.873,46.994 ccw(c0.909,46.085) 0,46.049 0,0.902 ccw(c0.964,0.964) 1.027,0 42.098,0 ccw(c42.074,0.926) 43,0.951 43,46.049 ccw(c42.074,46.074) 42.098,47 0.902,47

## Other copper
Top Layer:
  region net GND: 24.828,22.277 25.645,22.275 25.648,22.277 25.648,20.819 25.356,20.819 24.828,21.347
  pour cut-out: 21.047,26.077 24.542,26.077 24.542,22.577 21.037,22.577
  region net GND: 25.195,30.147 25.195,29.484 25.245,29.484 25.728,29.967
  region net GND: 25.014,28.15 24.514,27.65 25.221,27.65
  pour cut-out: 21.144,44.5 21.144,47 21.956,47 21.956,44.5
  pour cut-out: 19.514,18.956 19.514,16.434 24.096,16.434 24.096,18.924
  pour cut-out: 26.296,22.329 27.189,22.329 27.189,21.569 26.296,21.569
  pour cut-out: 19.725,26.666 20.613,26.666 20.555,26.284 19.777,26.284
  pour cut-out: 24.05,18.593 24.828,18.593 24.828,18.365 24.05,18.365
  pour cut-out: 18.5,21.768 19.537,21.768 19.537,20.296 18.5,20.296
  pour cut-out: 18.359,20.296 21.815,20.296 21.815,16.434 18.359,16.434
  region net GND: 22.434,20.215 21.29,20.215 21.29,18.615 22.433,18.615
  pour cut-out: 22,30.858 21.17,30.858 21.083,30.858 21.083,29.15 22,29.15
  pour cut-out: 19.448,34.855 21.17,34.855 21.17,33.995 19.448,33.995
  pour cut-out: 21.17,30.575 21.17,44.46 21.931,44.46 21.931,30.575
  pour cut-out: 13.865,24.825 13.617,24.577 13.617,23.738 14.647,22.708 15.261,22.708 15.261,24.823
  pour cut-out: 28.5,32.938 28.588,33.025 30.193,33.025 30.309,32.909 30.309,28.089 30.313,28.085 30.29,28.062 28.128,28.062 27.924,28.266 27.924,32.362

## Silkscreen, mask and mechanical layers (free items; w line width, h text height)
Top Overlay:
  text "K" at 1.802,41.914 h8
  text "H" at 7.287,41.725 h10
  text "J" at 31.675,41.686 h10
  text "MB2406A" at 30.963,39.013 h2.3
  text "I" at 36.528,2.655 h10
  text "E" at 1.565,1.953 h9
M1-Board Shape:
  the board outline again, w0.1
Drill Drawing:
  drawing of 166 lines, arcs and shapes, not listed
  text "PCB SPECIFICATIONS :" at -22.541,97.137 h3
  text "TG-150" at 51.675,93.175 h3
  text "A.   MATERIAL :" at -22.541,93.137 h3
  text "FR-4" at 15.959,93.137 h3
  text "TG-170" at 32.459,93.137 h3
  text "X   TG-140" at 66.1,93.1 h3
  text "B.   MATERIAL FAMILY :" at -22.541,90.137 h3
  text "VT-47" at 15.959,90.137 h3
  text "C.   SOLDERMASK COLOR :" at -22.541,87.137 h3
  text "GREEN" at 15.959,87.137 h3
  text "X  BLUE" at 32.459,87.137 h3
  text "RED" at 50.709,87.137 h3
  text "BLACK" at 66.709,87.137 h3
  text "D.   SILKSCREEN COLOR :" at -22.541,84.137 h3
  text "X  WHITE" at 15.959,84.137 h3
  text "YELLOW" at 32.459,84.137 h3
  text "BLACK" at 50.709,84.137 h3
  text "E.   SURFACE FINISH :" at -22.541,81.137 h3
  text "X  ENIG" at 15.959,81.137 h3
  text "IMMERSION SILVER" at 32.459,81.137 h3
  text "IMMERSION TIN" at 66.709,81.137 h3
  text "HASL" at 15.959,78.137 h3
  text "HASL (PB-FREE)" at 32.459,78.137 h3
  text "GOLDEN FINGER" at 66.709,78.137 h3
  text "F.   IMPEDANCE CONTROL :" at -22.541,75.137 h3
  text "NO" at 15.959,75.137 h3
  text "X  YES" at 32.459,75.137 h3
  text "G.   THROUGH VIA :" at -22.541,72.137 h3
  text "PLUG THE VIAS WHICH ARE COVERED WITH SOLDERMASK ONE OR TWO SIDE." at 15.959,72.137 h3
  text "PLUG MATERIAL :" at 15.959,69.137 h3
  text "X  SOLDERMASK" at 41.459,69.137 h3
  text "NON-CONDUCTIVE EPOXY." at 66.709,69.137 h3
  text "H.   STACK-UP :" at -22.541,66.137 h3
  text "SEE LAYER STACK-UP SEQUENCE FOR OVERALL THICKNESS." at 15.959,66.137 h3
  text "PCB : TYPE 3" at 110.088,57.996 h3
  text "ASPECT-RATIO, AXE Z :" at 110.088,52.496 h3
  text "6 :1 à 8 :1 / LEVEL \"B\"" at 110.107,45.749 h3
  text "Layer" at 50.841,44.7 h1.8
  text "Name" at 58.372,44.7 h1.8
  text "Material" at 72.928,44.7 h1.8
  text "Thickness" at 86.013,44.7 h1.8
  text "Constant" at 96.758,44.7 h1.8
  text "Top Overlay" at 58.372,41.1 h1.8
  text "Top Solder" at 58.372,37.5 h1.8
  text "Solder Resist" at 72.928,37.5 h1.8
  text "0,010mm" at 86.013,37.5 h1.8
  text "3.5" at 96.758,37.5 h1.8
  text "1" at 50.841,33.9 h1.8
  text "Top Layer" at 58.372,33.9 h1.8
  text "Copper" at 72.928,33.9 h1.8
  text "0,041mm" at 86.013,33.9 h1.8
  text "MINIMUN PARAMETERS" at 109.5,32.02 h3
  text "Dielectric 2" at 58.372,30.3 h1.8
  text "FR4" at 72.928,30.3 h1.8
  text "0,914mm" at 86.013,30.3 h1.8
  text "4.3" at 96.758,30.3 h1.8
  text "2" at 50.84,26.7 h1.8
  text "Bottom Layer" at 58.372,26.7 h1.8
  text "Copper" at 72.928,26.7 h1.8
  text "0,041mm" at 86.013,26.7 h1.8
  text "DEFAULT" at 109.5,26.52 h3
  text "Bottom Solder" at 58.372,23.1 h1.8
  text "Solder Resist" at 72.928,23.1 h1.8
  text "0,010mm" at 86.013,23.1 h1.8
  text "3.5" at 96.758,23.1 h1.8
  text "TRACKS : 0.150mm           / GAPS : 0.150mm" at 109.5,20.77 h3
  text "Bottom Overlay" at 58.372,19.5 h1.8
  text "Symbol" at 51.124,12.706 h2.16
  text "Count" at 59.586,12.706 h2.16
  text "Hole Size" at 68.364,12.706 h2.16
  text "Plated" at 83.806,12.706 h2.16
  text "Hole Type" at 91.234,12.706 h2.16
  text "Drill Layer Pair" at 102.049,12.706 h2.16
  text "Via/Pad" at 122.548,12.706 h2.16
  text "Hole Length" at 131.409,12.706 h2.16
  text "911" at 59.586,8.978 h1.8
  text "0,20mm (7,87mil)" at 68.364,8.978 h1.8
  text "PTH" at 83.806,8.978 h1.8
  text "Round" at 91.234,8.978 h1.8
  text "Top Layer - Bottom Layer" at 102.049,8.978 h1.8
  text "Via" at 122.548,8.978 h1.8
  text "-" at 131.409,8.978 h1.8
  text "2" at 59.586,5.25 h1.8
  text "1,00mm (39,37mil)" at 68.364,5.25 h1.8
  text "NPTH" at 83.806,5.25 h1.8
  text "Round" at 91.234,5.25 h1.8
  text "Top Layer - Bottom Layer" at 102.049,5.25 h1.8
  text "Pad" at 122.548,5.25 h1.8
  text "-" at 131.409,5.25 h1.8
  text "913 Total" at 59.586,1.522 h1.8

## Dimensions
1,0 to 1,47 on M2-Board Dimensions
0,1 to 43,1 on M2-Board Dimensions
